# Generated by FakeRAM 2.0
VERSION 5.7 ;
BUSBITCHARS "[]" ;
PROPERTYDEFINITIONS
  MACRO width INTEGER ;
  MACRO depth INTEGER ;
  MACRO banks INTEGER ;
END PROPERTYDEFINITIONS
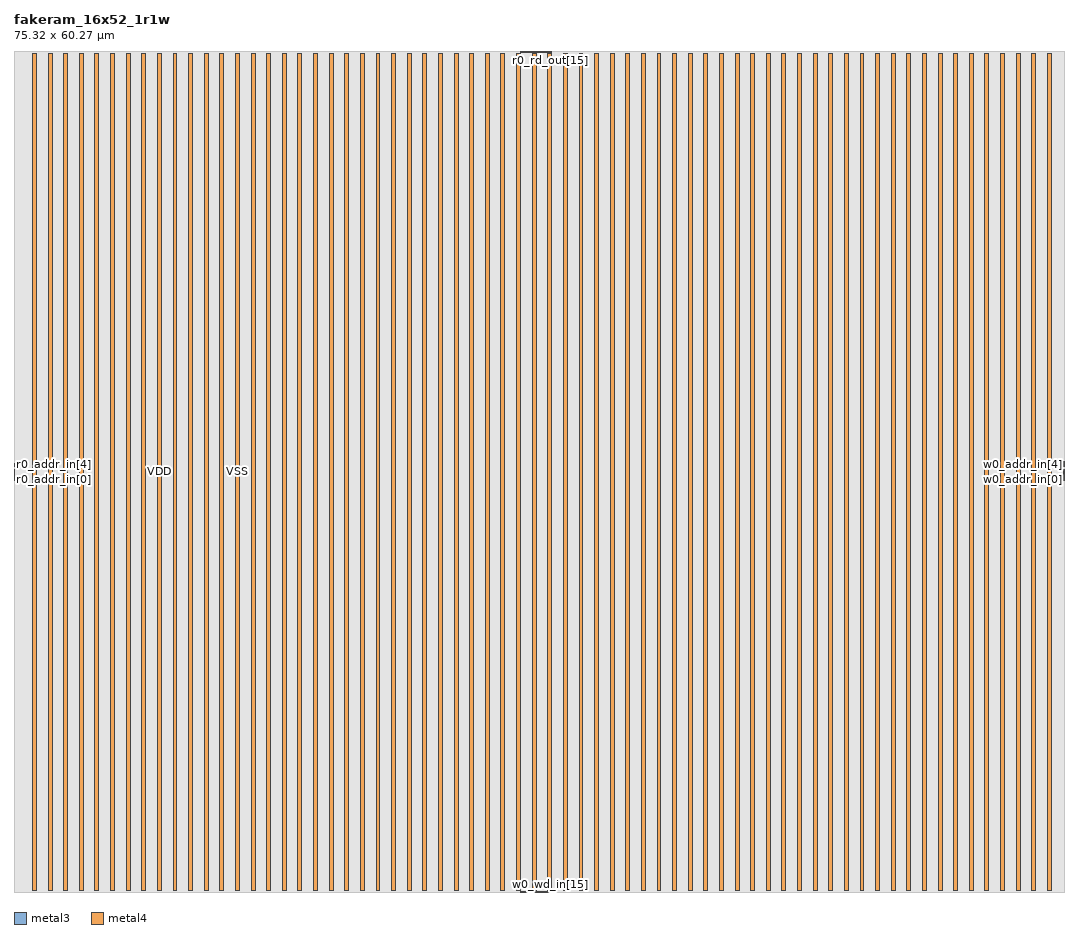
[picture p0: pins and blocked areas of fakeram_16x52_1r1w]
MACRO fakeram_16x52_1r1w
  PROPERTY width 16 ;
  PROPERTY depth 64 ;
  PROPERTY banks 1 ;
  FOREIGN fakeram_16x52_1r1w 0 0 ;
  SYMMETRY X Y R90 ;
  SIZE 75.320 BY 60.270 ;
  CLASS BLOCK ;
  PIN r0_addr_in[0]
    DIRECTION INPUT ;
    USE SIGNAL ;
    SHAPE ABUTMENT ;
    PORT
      LAYER metal3 ;
      RECT 0.000 29.540 0.070 29.610 ;
    END
  END r0_addr_in[0]
  PIN r0_addr_in[1]
    DIRECTION INPUT ;
    USE SIGNAL ;
    SHAPE ABUTMENT ;
    PORT
      LAYER metal3 ;
      RECT 0.000 29.680 0.070 29.750 ;
    END
  END r0_addr_in[1]
  PIN r0_addr_in[2]
    DIRECTION INPUT ;
    USE SIGNAL ;
    SHAPE ABUTMENT ;
    PORT
      LAYER metal3 ;
      RECT 0.000 29.820 0.070 29.890 ;
    END
  END r0_addr_in[2]
  PIN r0_addr_in[3]
    DIRECTION INPUT ;
    USE SIGNAL ;
    SHAPE ABUTMENT ;
    PORT
      LAYER metal3 ;
      RECT 0.000 29.960 0.070 30.030 ;
    END
  END r0_addr_in[3]
  PIN r0_addr_in[4]
    DIRECTION INPUT ;
    USE SIGNAL ;
    SHAPE ABUTMENT ;
    PORT
      LAYER metal3 ;
      RECT 0.000 30.100 0.070 30.170 ;
    END
  END r0_addr_in[4]
  PIN r0_addr_in[5]
    DIRECTION INPUT ;
    USE SIGNAL ;
    SHAPE ABUTMENT ;
    PORT
      LAYER metal3 ;
      RECT 0.000 30.240 0.070 30.310 ;
    END
  END r0_addr_in[5]
  PIN r0_ce_in
    DIRECTION INPUT ;
    USE SIGNAL ;
    SHAPE ABUTMENT ;
    PORT
      LAYER metal3 ;
      RECT 0.000 30.520 0.070 30.590 ;
    END
  END r0_ce_in
  PIN r0_clk
    DIRECTION INPUT ;
    USE SIGNAL ;
    SHAPE ABUTMENT ;
    PORT
      LAYER metal3 ;
      RECT 0.000 30.660 0.070 30.730 ;
    END
  END r0_clk
  PIN r0_rd_out[0]
    DIRECTION OUTPUT ;
    USE SIGNAL ;
    SHAPE ABUTMENT ;
    PORT
      LAYER metal3 ;
      RECT 36.365 60.200 36.435 60.270 ;
    END
  END r0_rd_out[0]
  PIN r0_rd_out[1]
    DIRECTION OUTPUT ;
    USE SIGNAL ;
    SHAPE ABUTMENT ;
    PORT
      LAYER metal3 ;
      RECT 36.505 60.200 36.575 60.270 ;
    END
  END r0_rd_out[1]
  PIN r0_rd_out[2]
    DIRECTION OUTPUT ;
    USE SIGNAL ;
    SHAPE ABUTMENT ;
    PORT
      LAYER metal3 ;
      RECT 36.645 60.200 36.715 60.270 ;
    END
  END r0_rd_out[2]
  PIN r0_rd_out[3]
    DIRECTION OUTPUT ;
    USE SIGNAL ;
    SHAPE ABUTMENT ;
    PORT
      LAYER metal3 ;
      RECT 36.785 60.200 36.855 60.270 ;
    END
  END r0_rd_out[3]
  PIN r0_rd_out[4]
    DIRECTION OUTPUT ;
    USE SIGNAL ;
    SHAPE ABUTMENT ;
    PORT
      LAYER metal3 ;
      RECT 36.925 60.200 36.995 60.270 ;
    END
  END r0_rd_out[4]
  PIN r0_rd_out[5]
    DIRECTION OUTPUT ;
    USE SIGNAL ;
    SHAPE ABUTMENT ;
    PORT
      LAYER metal3 ;
      RECT 37.065 60.200 37.135 60.270 ;
    END
  END r0_rd_out[5]
  PIN r0_rd_out[6]
    DIRECTION OUTPUT ;
    USE SIGNAL ;
    SHAPE ABUTMENT ;
    PORT
      LAYER metal3 ;
      RECT 37.205 60.200 37.275 60.270 ;
    END
  END r0_rd_out[6]
  PIN r0_rd_out[7]
    DIRECTION OUTPUT ;
    USE SIGNAL ;
    SHAPE ABUTMENT ;
    PORT
      LAYER metal3 ;
      RECT 37.345 60.200 37.415 60.270 ;
    END
  END r0_rd_out[7]
  PIN r0_rd_out[8]
    DIRECTION OUTPUT ;
    USE SIGNAL ;
    SHAPE ABUTMENT ;
    PORT
      LAYER metal3 ;
      RECT 37.485 60.200 37.555 60.270 ;
    END
  END r0_rd_out[8]
  PIN r0_rd_out[9]
    DIRECTION OUTPUT ;
    USE SIGNAL ;
    SHAPE ABUTMENT ;
    PORT
      LAYER metal3 ;
      RECT 37.625 60.200 37.695 60.270 ;
    END
  END r0_rd_out[9]
  PIN r0_rd_out[10]
    DIRECTION OUTPUT ;
    USE SIGNAL ;
    SHAPE ABUTMENT ;
    PORT
      LAYER metal3 ;
      RECT 37.765 60.200 37.835 60.270 ;
    END
  END r0_rd_out[10]
  PIN r0_rd_out[11]
    DIRECTION OUTPUT ;
    USE SIGNAL ;
    SHAPE ABUTMENT ;
    PORT
      LAYER metal3 ;
      RECT 37.905 60.200 37.975 60.270 ;
    END
  END r0_rd_out[11]
  PIN r0_rd_out[12]
    DIRECTION OUTPUT ;
    USE SIGNAL ;
    SHAPE ABUTMENT ;
    PORT
      LAYER metal3 ;
      RECT 38.045 60.200 38.115 60.270 ;
    END
  END r0_rd_out[12]
  PIN r0_rd_out[13]
    DIRECTION OUTPUT ;
    USE SIGNAL ;
    SHAPE ABUTMENT ;
    PORT
      LAYER metal3 ;
      RECT 38.185 60.200 38.255 60.270 ;
    END
  END r0_rd_out[13]
  PIN r0_rd_out[14]
    DIRECTION OUTPUT ;
    USE SIGNAL ;
    SHAPE ABUTMENT ;
    PORT
      LAYER metal3 ;
      RECT 38.325 60.200 38.395 60.270 ;
    END
  END r0_rd_out[14]
  PIN r0_rd_out[15]
    DIRECTION OUTPUT ;
    USE SIGNAL ;
    SHAPE ABUTMENT ;
    PORT
      LAYER metal3 ;
      RECT 38.465 60.200 38.535 60.270 ;
    END
  END r0_rd_out[15]
  PIN w0_addr_in[0]
    DIRECTION INPUT ;
    USE SIGNAL ;
    SHAPE ABUTMENT ;
    PORT
      LAYER metal3 ;
      RECT 75.250 29.540 75.320 29.610 ;
    END
  END w0_addr_in[0]
  PIN w0_addr_in[1]
    DIRECTION INPUT ;
    USE SIGNAL ;
    SHAPE ABUTMENT ;
    PORT
      LAYER metal3 ;
      RECT 75.250 29.680 75.320 29.750 ;
    END
  END w0_addr_in[1]
  PIN w0_addr_in[2]
    DIRECTION INPUT ;
    USE SIGNAL ;
    SHAPE ABUTMENT ;
    PORT
      LAYER metal3 ;
      RECT 75.250 29.820 75.320 29.890 ;
    END
  END w0_addr_in[2]
  PIN w0_addr_in[3]
    DIRECTION INPUT ;
    USE SIGNAL ;
    SHAPE ABUTMENT ;
    PORT
      LAYER metal3 ;
      RECT 75.250 29.960 75.320 30.030 ;
    END
  END w0_addr_in[3]
  PIN w0_addr_in[4]
    DIRECTION INPUT ;
    USE SIGNAL ;
    SHAPE ABUTMENT ;
    PORT
      LAYER metal3 ;
      RECT 75.250 30.100 75.320 30.170 ;
    END
  END w0_addr_in[4]
  PIN w0_addr_in[5]
    DIRECTION INPUT ;
    USE SIGNAL ;
    SHAPE ABUTMENT ;
    PORT
      LAYER metal3 ;
      RECT 75.250 30.240 75.320 30.310 ;
    END
  END w0_addr_in[5]
  PIN w0_we_in
    DIRECTION INPUT ;
    USE SIGNAL ;
    SHAPE ABUTMENT ;
    PORT
      LAYER metal3 ;
      RECT 75.250 30.520 75.320 30.590 ;
    END
  END w0_we_in
  PIN w0_ce_in
    DIRECTION INPUT ;
    USE SIGNAL ;
    SHAPE ABUTMENT ;
    PORT
      LAYER metal3 ;
      RECT 75.250 30.660 75.320 30.730 ;
    END
  END w0_ce_in
  PIN w0_clk
    DIRECTION INPUT ;
    USE SIGNAL ;
    SHAPE ABUTMENT ;
    PORT
      LAYER metal3 ;
      RECT 75.250 30.800 75.320 30.870 ;
    END
  END w0_clk
  PIN w0_wd_in[0]
    DIRECTION INPUT ;
    USE SIGNAL ;
    SHAPE ABUTMENT ;
    PORT
      LAYER metal3 ;
      RECT 36.365 0.000 36.435 0.070 ;
    END
  END w0_wd_in[0]
  PIN w0_wd_in[1]
    DIRECTION INPUT ;
    USE SIGNAL ;
    SHAPE ABUTMENT ;
    PORT
      LAYER metal3 ;
      RECT 36.505 0.000 36.575 0.070 ;
    END
  END w0_wd_in[1]
  PIN w0_wd_in[2]
    DIRECTION INPUT ;
    USE SIGNAL ;
    SHAPE ABUTMENT ;
    PORT
      LAYER metal3 ;
      RECT 36.645 0.000 36.715 0.070 ;
    END
  END w0_wd_in[2]
  PIN w0_wd_in[3]
    DIRECTION INPUT ;
    USE SIGNAL ;
    SHAPE ABUTMENT ;
    PORT
      LAYER metal3 ;
      RECT 36.785 0.000 36.855 0.070 ;
    END
  END w0_wd_in[3]
  PIN w0_wd_in[4]
    DIRECTION INPUT ;
    USE SIGNAL ;
    SHAPE ABUTMENT ;
    PORT
      LAYER metal3 ;
      RECT 36.925 0.000 36.995 0.070 ;
    END
  END w0_wd_in[4]
  PIN w0_wd_in[5]
    DIRECTION INPUT ;
    USE SIGNAL ;
    SHAPE ABUTMENT ;
    PORT
      LAYER metal3 ;
      RECT 37.065 0.000 37.135 0.070 ;
    END
  END w0_wd_in[5]
  PIN w0_wd_in[6]
    DIRECTION INPUT ;
    USE SIGNAL ;
    SHAPE ABUTMENT ;
    PORT
      LAYER metal3 ;
      RECT 37.205 0.000 37.275 0.070 ;
    END
  END w0_wd_in[6]
  PIN w0_wd_in[7]
    DIRECTION INPUT ;
    USE SIGNAL ;
    SHAPE ABUTMENT ;
    PORT
      LAYER metal3 ;
      RECT 37.345 0.000 37.415 0.070 ;
    END
  END w0_wd_in[7]
  PIN w0_wd_in[8]
    DIRECTION INPUT ;
    USE SIGNAL ;
    SHAPE ABUTMENT ;
    PORT
      LAYER metal3 ;
      RECT 37.485 0.000 37.555 0.070 ;
    END
  END w0_wd_in[8]
  PIN w0_wd_in[9]
    DIRECTION INPUT ;
    USE SIGNAL ;
    SHAPE ABUTMENT ;
    PORT
      LAYER metal3 ;
      RECT 37.625 0.000 37.695 0.070 ;
    END
  END w0_wd_in[9]
  PIN w0_wd_in[10]
    DIRECTION INPUT ;
    USE SIGNAL ;
    SHAPE ABUTMENT ;
    PORT
      LAYER metal3 ;
      RECT 37.765 0.000 37.835 0.070 ;
    END
  END w0_wd_in[10]
  PIN w0_wd_in[11]
    DIRECTION INPUT ;
    USE SIGNAL ;
    SHAPE ABUTMENT ;
    PORT
      LAYER metal3 ;
      RECT 37.905 0.000 37.975 0.070 ;
    END
  END w0_wd_in[11]
  PIN w0_wd_in[12]
    DIRECTION INPUT ;
    USE SIGNAL ;
    SHAPE ABUTMENT ;
    PORT
      LAYER metal3 ;
      RECT 38.045 0.000 38.115 0.070 ;
    END
  END w0_wd_in[12]
  PIN w0_wd_in[13]
    DIRECTION INPUT ;
    USE SIGNAL ;
    SHAPE ABUTMENT ;
    PORT
      LAYER metal3 ;
      RECT 38.185 0.000 38.255 0.070 ;
    END
  END w0_wd_in[13]
  PIN w0_wd_in[14]
    DIRECTION INPUT ;
    USE SIGNAL ;
    SHAPE ABUTMENT ;
    PORT
      LAYER metal3 ;
      RECT 38.325 0.000 38.395 0.070 ;
    END
  END w0_wd_in[14]
  PIN w0_wd_in[15]
    DIRECTION INPUT ;
    USE SIGNAL ;
    SHAPE ABUTMENT ;
    PORT
      LAYER metal3 ;
      RECT 38.465 0.000 38.535 0.070 ;
    END
  END w0_wd_in[15]
  PIN VSS
    DIRECTION INOUT ;
    USE GROUND ;
    PORT
      LAYER metal4 ;
      RECT 2.450 0.140 2.730 60.130 ;
      RECT 4.690 0.140 4.970 60.130 ;
      RECT 6.930 0.140 7.210 60.130 ;
      RECT 9.170 0.140 9.450 60.130 ;
      RECT 11.410 0.140 11.690 60.130 ;
      RECT 13.650 0.140 13.930 60.130 ;
      RECT 15.890 0.140 16.170 60.130 ;
      RECT 18.130 0.140 18.410 60.130 ;
      RECT 20.370 0.140 20.650 60.130 ;
      RECT 22.610 0.140 22.890 60.130 ;
      RECT 24.850 0.140 25.130 60.130 ;
      RECT 27.090 0.140 27.370 60.130 ;
      RECT 29.330 0.140 29.610 60.130 ;
      RECT 31.570 0.140 31.850 60.130 ;
      RECT 33.810 0.140 34.090 60.130 ;
      RECT 36.050 0.140 36.330 60.130 ;
      RECT 38.290 0.140 38.570 60.130 ;
      RECT 40.530 0.140 40.810 60.130 ;
      RECT 42.770 0.140 43.050 60.130 ;
      RECT 45.010 0.140 45.290 60.130 ;
      RECT 47.250 0.140 47.530 60.130 ;
      RECT 49.490 0.140 49.770 60.130 ;
      RECT 51.730 0.140 52.010 60.130 ;
      RECT 53.970 0.140 54.250 60.130 ;
      RECT 56.210 0.140 56.490 60.130 ;
      RECT 58.450 0.140 58.730 60.130 ;
      RECT 60.690 0.140 60.970 60.130 ;
      RECT 62.930 0.140 63.210 60.130 ;
      RECT 65.170 0.140 65.450 60.130 ;
      RECT 67.410 0.140 67.690 60.130 ;
      RECT 69.650 0.140 69.930 60.130 ;
      RECT 71.890 0.140 72.170 60.130 ;
      RECT 74.130 0.140 74.410 60.130 ;
    END
  END VSS
  PIN VDD
    DIRECTION INOUT ;
    USE POWER ;
    PORT
      LAYER metal4 ;
      RECT 1.330 0.140 1.610 60.130 ;
      RECT 3.570 0.140 3.850 60.130 ;
      RECT 5.810 0.140 6.090 60.130 ;
      RECT 8.050 0.140 8.330 60.130 ;
      RECT 10.290 0.140 10.570 60.130 ;
      RECT 12.530 0.140 12.810 60.130 ;
      RECT 14.770 0.140 15.050 60.130 ;
      RECT 17.010 0.140 17.290 60.130 ;
      RECT 19.250 0.140 19.530 60.130 ;
      RECT 21.490 0.140 21.770 60.130 ;
      RECT 23.730 0.140 24.010 60.130 ;
      RECT 25.970 0.140 26.250 60.130 ;
      RECT 28.210 0.140 28.490 60.130 ;
      RECT 30.450 0.140 30.730 60.130 ;
      RECT 32.690 0.140 32.970 60.130 ;
      RECT 34.930 0.140 35.210 60.130 ;
      RECT 37.170 0.140 37.450 60.130 ;
      RECT 39.410 0.140 39.690 60.130 ;
      RECT 41.650 0.140 41.930 60.130 ;
      RECT 43.890 0.140 44.170 60.130 ;
      RECT 46.130 0.140 46.410 60.130 ;
      RECT 48.370 0.140 48.650 60.130 ;
      RECT 50.610 0.140 50.890 60.130 ;
      RECT 52.850 0.140 53.130 60.130 ;
      RECT 55.090 0.140 55.370 60.130 ;
      RECT 57.330 0.140 57.610 60.130 ;
      RECT 59.570 0.140 59.850 60.130 ;
      RECT 61.810 0.140 62.090 60.130 ;
      RECT 64.050 0.140 64.330 60.130 ;
      RECT 66.290 0.140 66.570 60.130 ;
      RECT 68.530 0.140 68.810 60.130 ;
      RECT 70.770 0.140 71.050 60.130 ;
      RECT 73.010 0.140 73.290 60.130 ;
    END
  END VDD
  OBS
    LAYER metal1 ;
    RECT 0 0 75.320 60.270 ;
    LAYER metal2 ;
    RECT 0 0 75.320 60.270 ;
    LAYER metal3 ;
    RECT 0 0 75.320 60.270 ;
    LAYER metal4 ;
    RECT 0 0 75.320 60.270 ;
    LAYER OVERLAP ;
    RECT 0 0 75.320 60.270 ;
  END
END fakeram_16x52_1r1w

END LIBRARY
